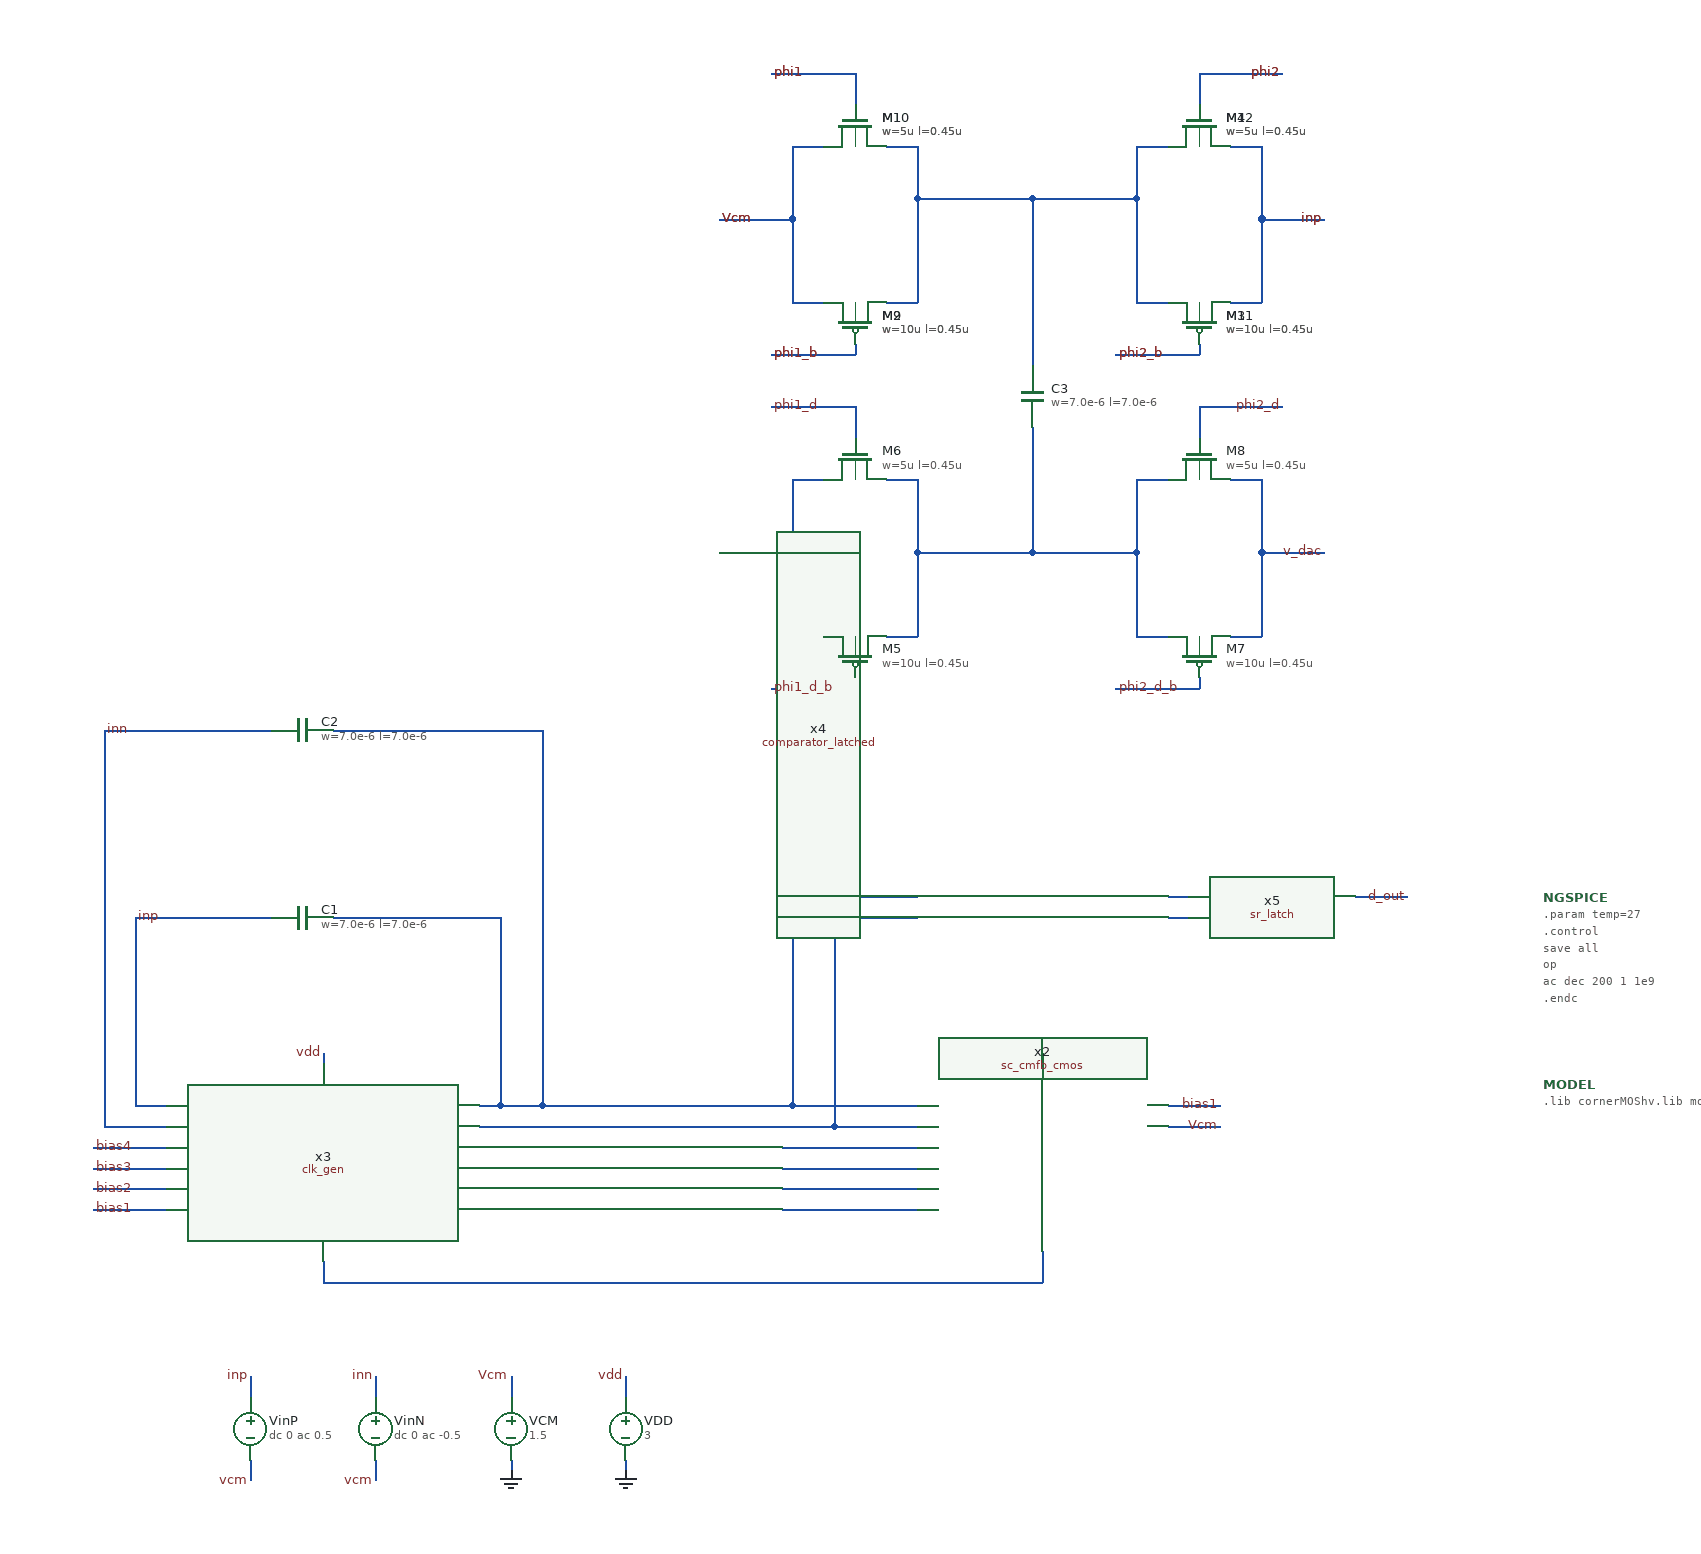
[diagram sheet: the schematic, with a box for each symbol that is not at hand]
v {xschem version=3.4.6 file_version=1.2}
G {}
K {}
V {}
S {}
E {}
N 10 200 10 220 {lab=Vcm}
N 10 280 10 290 {lab=GND}
N -240 280 -240 300 {lab=vcm}
N -120 280 -120 300 {lab=vcm}
N -120 200 -120 220 {lab=inn}
N -240 200 -240 220 {lab=inp}
N 120 280 120 290 {lab=GND}
N 120 200 120 220 {lab=vdd}
N -170 -110 -170 -100 {lab=vdd}
N 640 -60 690 -60 {lab=bias1}
N -390 40 -320 40 {lab=bias1}
N -390 20 -320 20 {lab=bias2}
N -390 0 -320 0 {lab=bias3}
N -390 -20 -320 -20 {lab=bias4}
N 520 -110 520 -100 {lab=#net1}
N 640 -40 690 -40 {lab=Vcm}
N 270 40 400 40 {lab=#net2}
N 270 20 400 20 {lab=#net3}
N 270 -0 400 0 {lab=#net4}
N 270 -20 400 -20 {lab=#net5}
N 320 -40 400 -40 {lab=#net6}
N 280 -60 400 -60 {lab=#net7}
N -350 -60 -320 -60 {lab=inp}
N -350 -240 -350 -60 {lab=inp}
N -350 -240 -220 -240 {lab=inp}
N -380 -40 -320 -40 {lab=inn}
N -380 -420 -380 -40 {lab=inn}
N -380 -420 -220 -420 {lab=inn}
N -160 -240 -0 -240 {lab=#net7}
N 0 -240 -0 -60 {lab=#net7}
N -20 -60 -0 -60 {lab=#net7}
N -160 -420 40 -420 {lab=#net7}
N 40 -420 40 -60 {lab=#net7}
N -0 -60 40 -60 {lab=#net7}
N 280 -260 400 -260 {lab=#net7}
N 280 -260 280 -60 {lab=#net7}
N 40 -60 280 -60 {lab=#net7}
N 320 -240 400 -240 {lab=#net6}
N 320 -240 320 -40 {lab=#net6}
N -20 -40 320 -40 {lab=#net6}
N 640 -260 660 -260 {lab=#net8}
N 640 -240 660 -240 {lab=#net9}
N -170 90 -170 110 {lab=#net10}
N -170 110 520 110 {lab=#net10}
N 520 80 520 110 {lab=#net10}
N 280 -980 310 -980 {lab=Vcm}
N 280 -830 310 -830 {lab=Vcm}
N 370 -980 400 -980 {lab=#net11}
N 370 -830 400 -830 {lab=#net11}
N 340 -790 340 -780 {lab=phi1_b}
N 340 -1050 340 -1020 {lab=phi1}
N 280 -910 280 -830 {lab=Vcm}
N 400 -930 400 -830 {lab=#net11}
N 610 -980 640 -980 {lab=#net11}
N 610 -830 640 -830 {lab=#net11}
N 700 -980 730 -980 {lab=inp}
N 700 -830 730 -830 {lab=inp}
N 670 -790 670 -780 {lab=phi2_b}
N 670 -1050 670 -1020 {lab=phi2}
N 610 -930 610 -830 {lab=#net11}
N 730 -910 730 -830 {lab=inp}
N 260 -780 340 -780 {lab=phi1_b}
N 260 -1050 340 -1050 {lab=phi1}
N 210 -910 280 -910 {lab=Vcm}
N 280 -980 280 -910 {lab=Vcm}
N 730 -910 790 -910 {lab=inp}
N 730 -980 730 -910 {lab=inp}
N 670 -1050 750 -1050 {lab=phi2}
N 510 -930 610 -930 {lab=#net11}
N 400 -980 400 -930 {lab=#net11}
N 610 -980 610 -930 {lab=#net11}
N 510 -930 510 -770 {lab=#net11}
N 400 -930 510 -930 {lab=#net11}
N 590 -780 670 -780 {lab=phi2_b}
N 280 -660 310 -660 {lab=#net12}
N 280 -510 310 -510 {lab=#net12}
N 370 -660 400 -660 {lab=#net13}
N 370 -510 400 -510 {lab=#net13}
N 340 -470 340 -460 {lab=phi1_d_b}
N 340 -730 340 -700 {lab=phi1_d}
N 280 -590 280 -510 {lab=#net12}
N 610 -660 640 -660 {lab=#net13}
N 610 -510 640 -510 {lab=#net13}
N 700 -660 730 -660 {lab=v_dac}
N 700 -510 730 -510 {lab=v_dac}
N 670 -470 670 -460 {lab=phi2_d_b}
N 670 -730 670 -700 {lab=phi2_d}
N 730 -590 730 -510 {lab=v_dac}
N 260 -460 340 -460 {lab=phi1_d_b}
N 260 -730 340 -730 {lab=phi1_d}
N 210 -590 280 -590 {lab=#net12}
N 280 -660 280 -590 {lab=#net12}
N 730 -590 790 -590 {lab=v_dac}
N 730 -660 730 -590 {lab=v_dac}
N 670 -730 750 -730 {lab=phi2_d}
N 400 -590 400 -510 {lab=#net13}
N 610 -590 610 -510 {lab=#net13}
N 590 -460 670 -460 {lab=phi2_d_b}
N 510 -710 510 -590 {lab=#net13}
N 400 -590 510 -590 {lab=#net13}
N 400 -660 400 -590 {lab=#net13}
N 510 -590 610 -590 {lab=#net13}
N 610 -660 610 -590 {lab=#net13}
N 820 -260 870 -260 {lab=v_dac}
C {vsource.sym} 10 250 0 0 {name=VCM value=1.5 savecurrent=false}
C {lab_pin.sym} 10 200 0 0 {name=p1 sig_type=std_logic lab=Vcm}
C {gnd.sym} 10 290 0 0 {name=l2 lab=GND}
C {vsource.sym} -240 250 0 0 {name=VinP value="dc 0 ac 0.5"}
C {vsource.sym} -120 250 0 0 {name=VinN value="dc 0 ac -0.5" }
C {lab_pin.sym} -120 200 0 0 {name=p3 sig_type=std_logic lab=inn}
C {lab_pin.sym} -240 300 0 0 {name=p4 sig_type=std_logic lab=vcm}
C {lab_pin.sym} -120 300 0 0 {name=p5 sig_type=std_logic lab=vcm}
C {vsource.sym} 120 250 0 0 {name=VDD value=3 savecurrent=false}
C {gnd.sym} 120 290 0 0 {name=l11 lab=GND}
C {lab_pin.sym} 120 200 0 0 {name=p24 sig_type=std_logic lab=vdd}
C {code_shown.sym} 1000 -260 0 0 {name=NGSPICE only_toplevel=false 
value="
.param temp=27
.control
save all
op
ac dec 200 1 1e9
.endc
"}
C {devices/code_shown.sym} 1000 -80 0 0 {name=MODEL only_toplevel=true
format="tcleval( @value )"
value=".lib cornerMOShv.lib mos_tt
"}
C {ota_folded_cascoded.sym} -170 20 0 0 {name=x1}
C {lab_pin.sym} -170 -110 0 0 {name=p17 sig_type=std_logic lab=vdd}
C {sc_cmfb_cmos.sym} 520 0 0 0 {name=x2}
C {lab_wire.sym} -390 40 0 1 {name=p25 sig_type=std_logic lab=bias1}
C {lab_wire.sym} 690 -40 0 0 {name=p15 sig_type=std_logic lab=Vcm}
C {lab_wire.sym} 690 -60 0 0 {name=p16 sig_type=std_logic lab=bias1}
C {lab_wire.sym} -390 20 0 1 {name=p22 sig_type=std_logic lab=bias2}
C {lab_wire.sym} -390 0 0 1 {name=p26 sig_type=std_logic lab=bias3}
C {lab_wire.sym} -390 -20 0 1 {name=p27 sig_type=std_logic lab=bias4}
C {lab_pin.sym} -240 200 0 0 {name=p6 sig_type=std_logic lab=inp}
C {clk_gen.sym} 220 10 0 0 {name=x3}
C {sg13g2_pr/cap_cmim.sym} -190 -240 3 1 {name=C1
model=cap_cmim
w=7.0e-6
l=7.0e-6
m=1
spiceprefix=X}
C {sg13g2_pr/cap_cmim.sym} -190 -420 3 1 {name=C2
model=cap_cmim
w=7.0e-6
l=7.0e-6
m=1
spiceprefix=X}
C {comparator_latched.sym} 550 -230 0 0 {name=x4}
C {sr_latch.sym} 740 -250 0 0 {name=x5}
C {sg13g2_pr/sg13_hv_pmos.sym} 340 -810 3 0 {name=M2
l=0.45u
w=10u
ng=1
m=1
model=sg13_hv_pmos
spiceprefix=X
}
C {sg13g2_pr/sg13_hv_nmos.sym} 340 -1000 1 0 {name=M1
l=0.45u
w=5u
ng=1
m=1
model=sg13_hv_nmos
spiceprefix=X
}
C {sg13g2_pr/sg13_hv_pmos.sym} 670 -810 3 0 {name=M3
l=0.45u
w=10u
ng=1
m=1
model=sg13_hv_pmos
spiceprefix=X
}
C {sg13g2_pr/sg13_hv_nmos.sym} 670 -1000 1 0 {name=M4
l=0.45u
w=5u
ng=1
m=1
model=sg13_hv_nmos
spiceprefix=X
}
C {lab_wire.sym} 210 -910 0 1 {name=p10 sig_type=std_logic lab=Vcm}
C {lab_wire.sym} -350 -240 0 1 {name=p11 sig_type=std_logic lab=inp}
C {lab_wire.sym} -380 -420 0 1 {name=p12 sig_type=std_logic lab=inn}
C {lab_wire.sym} 790 -910 0 0 {name=p13 sig_type=std_logic lab=inp}
C {lab_wire.sym} 590 -780 0 1 {name=p8 sig_type=std_logic lab=phi2_b}
C {lab_wire.sym} 750 -1050 0 0 {name=p9 sig_type=std_logic lab=phi2}
C {lab_wire.sym} 260 -1050 0 1 {name=p2 sig_type=std_logic lab=phi1}
C {lab_wire.sym} 260 -780 0 1 {name=p7 sig_type=std_logic lab=phi1_b}
C {sg13g2_pr/sg13_hv_pmos.sym} 340 -490 3 0 {name=M5
l=0.45u
w=10u
ng=1
m=1
model=sg13_hv_pmos
spiceprefix=X
}
C {sg13g2_pr/sg13_hv_nmos.sym} 340 -680 1 0 {name=M6
l=0.45u
w=5u
ng=1
m=1
model=sg13_hv_nmos
spiceprefix=X
}
C {sg13g2_pr/sg13_hv_pmos.sym} 670 -490 3 0 {name=M7
l=0.45u
w=10u
ng=1
m=1
model=sg13_hv_pmos
spiceprefix=X
}
C {sg13g2_pr/sg13_hv_nmos.sym} 670 -680 1 0 {name=M8
l=0.45u
w=5u
ng=1
m=1
model=sg13_hv_nmos
spiceprefix=X
}
C {lab_wire.sym} 590 -460 0 1 {name=p19 sig_type=std_logic lab=phi2_d_b}
C {lab_wire.sym} 750 -730 0 0 {name=p20 sig_type=std_logic lab=phi2_d}
C {lab_wire.sym} 260 -730 0 1 {name=p21 sig_type=std_logic lab=phi1_d}
C {lab_wire.sym} 260 -460 0 1 {name=p23 sig_type=std_logic lab=phi1_d_b}
C {sg13g2_pr/sg13_hv_pmos.sym} 340 -810 3 0 {name=M9
l=0.45u
w=10u
ng=1
m=1
model=sg13_hv_pmos
spiceprefix=X
}
C {sg13g2_pr/sg13_hv_nmos.sym} 340 -1000 1 0 {name=M10
l=0.45u
w=5u
ng=1
m=1
model=sg13_hv_nmos
spiceprefix=X
}
C {sg13g2_pr/cap_cmim.sym} 510 -740 0 1 {name=C3
model=cap_cmim
w=7.0e-6
l=7.0e-6
m=1
spiceprefix=X}
C {sg13g2_pr/sg13_hv_pmos.sym} 670 -810 3 0 {name=M11
l=0.45u
w=10u
ng=1
m=1
model=sg13_hv_pmos
spiceprefix=X
}
C {sg13g2_pr/sg13_hv_nmos.sym} 670 -1000 1 0 {name=M12
l=0.45u
w=5u
ng=1
m=1
model=sg13_hv_nmos
spiceprefix=X
}
C {lab_wire.sym} 210 -910 0 1 {name=p14 sig_type=std_logic lab=Vcm}
C {lab_wire.sym} 790 -910 0 0 {name=p18 sig_type=std_logic lab=inp}
C {lab_wire.sym} 590 -780 0 1 {name=p28 sig_type=std_logic lab=phi2_b}
C {lab_wire.sym} 750 -1050 0 0 {name=p29 sig_type=std_logic lab=phi2}
C {lab_wire.sym} 260 -1050 0 1 {name=p30 sig_type=std_logic lab=phi1}
C {lab_wire.sym} 260 -780 0 1 {name=p31 sig_type=std_logic lab=phi1_b}
C {lab_wire.sym} 790 -590 0 0 {name=p32 sig_type=std_logic lab=v_dac}
C {lab_wire.sym} 870 -260 0 0 {name=p33 sig_type=std_logic lab=d_out}
